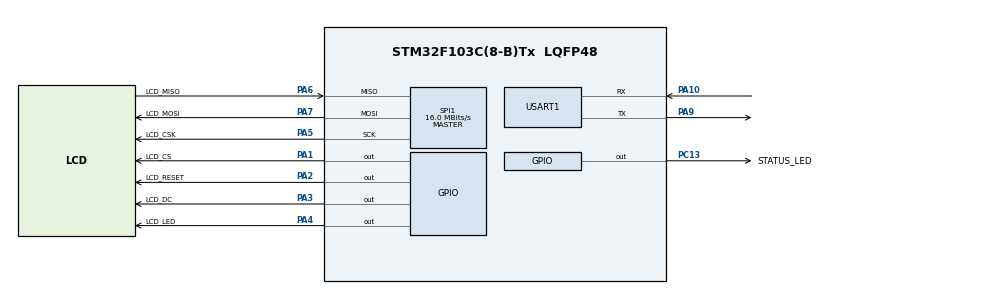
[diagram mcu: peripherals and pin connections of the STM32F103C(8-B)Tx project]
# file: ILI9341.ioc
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Dma.Request0=SPI1_TX
Dma.SPI1_TX.0.Direction=DMA_MEMORY_TO_PERIPH
Dma.SPI1_TX.0.Instance=DMA1_Channel3
Dma.SPI1_TX.0.MemDataAlignment=DMA_MDATAALIGN_BYTE
Dma.SPI1_TX.0.MemInc=DMA_MINC_ENABLE
Dma.SPI1_TX.0.Mode=DMA_NORMAL
Dma.SPI1_TX.0.PeriphDataAlignment=DMA_PDATAALIGN_BYTE
Dma.SPI1_TX.0.PeriphInc=DMA_PINC_DISABLE
Dma.SPI1_TX.0.Priority=DMA_PRIORITY_HIGH
Mcu.Family=STM32F1
Mcu.Name=STM32F103C(8-B)Tx
Mcu.Package=LQFP48
NVIC.DMA1_Channel3_IRQn=true\:0\:0\:false\:false\:true
NVIC.PriorityGroup=NVIC_PRIORITYGROUP_4
PA1.GPIO_Label=LCD_CS
PA1.Signal=GPIO_Output
PA10.Mode=Asynchronous
PA10.Signal=USART1_RX
PA13.Mode=Serial_Wire
PA13.Signal=SYS_JTMS-SWDIO
PA14.Mode=Serial_Wire
PA14.Signal=SYS_JTCK-SWCLK
PA2.GPIO_Label=LCD_RESET
PA2.PinState=GPIO_PIN_RESET
PA2.Signal=GPIO_Output
PA3.GPIO_Label=LCD_DC
PA3.PinState=GPIO_PIN_RESET
PA3.Signal=GPIO_Output
PA4.GPIO_Label=LCD_LED
PA4.Signal=GPIO_Output
PA5.GPIO_Label=LCD_CSK
PA5.Mode=Full_Duplex_Master
PA5.Signal=SPI1_SCK
PA6.GPIO_Label=LCD_MISO
PA6.Mode=Full_Duplex_Master
PA6.Signal=SPI1_MISO
PA7.GPIO_Label=LCD_MOSI
PA7.Mode=Full_Duplex_Master
PA7.Signal=SPI1_MOSI
PA9.Mode=Asynchronous
PA9.Signal=USART1_TX
PC13-TAMPER-RTC.GPIO_Label=STATUS_LED
PC13-TAMPER-RTC.Signal=GPIO_Output
ProjectManager.HeapSize=0x200
ProjectManager.StackSize=0x400
ProjectManager.TargetToolchain=Makefile
RCC.AHBFreq_Value=64000000
RCC.APB1CLKDivider=RCC_HCLK_DIV2
RCC.APB1Freq_Value=32000000
RCC.APB1TimFreq_Value=64000000
RCC.APB2Freq_Value=64000000
RCC.APB2TimFreq_Value=64000000
RCC.HCLKFreq_Value=64000000
RCC.PLLMUL=RCC_PLL_MUL16
RCC.SYSCLKFreq_VALUE=64000000
RCC.SYSCLKSource=RCC_SYSCLKSOURCE_PLLCLK
RCC.USBFreq_Value=64000000
SPI1.BaudRatePrescaler=SPI_BAUDRATEPRESCALER_4
SPI1.CalculateBaudRate=16.0 MBits/s
SPI1.Direction=SPI_DIRECTION_2LINES
SPI1.Mode=SPI_MODE_MASTER
SPI1.VirtualType=VM_MASTER
USART1.VirtualMode=VM_ASYNC
board=ILI9341

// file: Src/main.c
/**
  ******************************************************************************
  * File Name          : main.c
  * Description        : Main program body
  ******************************************************************************
  ** This notice applies to any and all portions of this file
  * that are not between comment pairs USER CODE BEGIN and
  * USER CODE END. Other portions of this file, whether
  * inserted by the user or by software development tools
  * are owned by their respective copyright owners.
  *
  * COPYRIGHT(c) 2017 STMicroelectronics
  *
  * Redistribution and use in source and binary forms, with or without modification,
  * are permitted provided that the following conditions are met:
  *   1. Redistributions of source code must retain the above copyright notice,
  *      this list of conditions and the following disclaimer.
  *   2. Redistributions in binary form must reproduce the above copyright notice,
  *      this list of conditions and the following disclaimer in the documentation
  *      and/or other materials provided with the distribution.
  *   3. Neither the name of STMicroelectronics nor the names of its contributors
  *      may be used to endorse or promote products derived from this software
  *      without specific prior written permission.
  *
  * THIS SOFTWARE IS PROVIDED BY THE COPYRIGHT HOLDERS AND CONTRIBUTORS "AS IS"
  * AND ANY EXPRESS OR IMPLIED WARRANTIES, INCLUDING, BUT NOT LIMITED TO, THE
  * IMPLIED WARRANTIES OF MERCHANTABILITY AND FITNESS FOR A PARTICULAR PURPOSE ARE
  * DISCLAIMED. IN NO EVENT SHALL THE COPYRIGHT HOLDER OR CONTRIBUTORS BE LIABLE
  * FOR ANY DIRECT, INDIRECT, INCIDENTAL, SPECIAL, EXEMPLARY, OR CONSEQUENTIAL
  * DAMAGES (INCLUDING, BUT NOT LIMITED TO, PROCUREMENT OF SUBSTITUTE GOODS OR
  * SERVICES; LOSS OF USE, DATA, OR PROFITS; OR BUSINESS INTERRUPTION) HOWEVER
  * CAUSED AND ON ANY THEORY OF LIABILITY, WHETHER IN CONTRACT, STRICT LIABILITY,
  * OR TORT (INCLUDING NEGLIGENCE OR OTHERWISE) ARISING IN ANY WAY OUT OF THE USE
  * OF THIS SOFTWARE, EVEN IF ADVISED OF THE POSSIBILITY OF SUCH DAMAGE.
  *
  ******************************************************************************
  */
#include "main.h"
#include "stm32f1xx_hal.h"
#include "spi.h"
#include "usart.h"
#include "gpio.h"

/* USER CODE BEGIN Includes */
#include <math.h>
#include "ILI9341.h"

#define M_PI 3.14159

void stled_on(void) {
    HAL_GPIO_WritePin(STATUS_LED_GPIO_Port, STATUS_LED_Pin, GPIO_PIN_SET);
}

void stled_off(void) {
    HAL_GPIO_WritePin(STATUS_LED_GPIO_Port, STATUS_LED_Pin, GPIO_PIN_RESET);
}

/* USER CODE END Includes */

/* USER CODE BEGIN PV */
/* Private variables ---------------------------------------------------------*/

/* USER CODE END PV */

void SystemClock_Config(void);

/* USER CODE BEGIN PFP */
/* Private function prototypes -----------------------------------------------*/

/* USER CODE END PFP */

int main(void)
{

  /* MCU Configuration----------------------------------------------------------*/

  /* Reset of all peripherals, Initializes the Flash interface and the Systick. */
  HAL_Init();

  /* Configure the system clock */
  SystemClock_Config();

  /* Initialize all configured peripherals */
  MX_GPIO_Init();
  MX_SPI1_Init();
  MX_USART1_UART_Init();

  /* USER CODE BEGIN 2 */
  lcd_reset();
  HAL_GPIO_WritePin(GPIOA, LCD_LED_Pin, GPIO_PIN_SET);
  ILI9341_begin(&hspi1);
  ILI9341_setRotation(3);

  /* USER CODE END 2 */

  /* Infinite loop */
  /* USER CODE BEGIN WHILE */
  while (1)
  {
    ILI9341_begin(&hspi1);
    ILI9341_setRotation(3);
  /* USER CODE END WHILE */

  /* USER CODE BEGIN 3 */
    for(uint16_t i = 5; i<315; i+=30)
    {
      ILI9341_drawLine( i, 5, i, 235, ILI9341_OLIVE);
    }
    for(uint16_t i = 5; i<315; i+=30)
    {
      ILI9341_drawLine( 5, i, 315, i, ILI9341_OLIVE);
    }

    for(float i = 0; i < 320; i+=0.2) // count point
    {
      ILI9341_fillCircle(i, 80*sin(30*0.2*M_PI*i/180)+120, 1, ILI9341_GREEN);
      ILI9341_fillCircle(i-50, 80*sin(30*0.2*M_PI*i/180)+120, 1, ILI9341_BLUE);
      ILI9341_fillCircle(i-25, 80*cos(30*M_PI*0.1*i/180)+120, 1, ILI9341_RED);
      ILI9341_fillCircle(i-25, 80*sin(30*M_PI*0.1*i/180)+120, 1, ILI9341_CYAN);
      ILI9341_fillCircle(i, 80*cos(30*0.2*M_PI*i/180)+120, 1, ILI9341_YELLOW);
    }
    lcd_reset();
  }

  /* USER CODE END 3 */

}

/** System Clock Configuration
*/
void SystemClock_Config(void)
{

  RCC_OscInitTypeDef RCC_OscInitStruct;
  RCC_ClkInitTypeDef RCC_ClkInitStruct;

    /**Initializes the CPU, AHB and APB busses clocks
    */
  RCC_OscInitStruct.OscillatorType = RCC_OSCILLATORTYPE_HSI;
  RCC_OscInitStruct.HSIState = RCC_HSI_ON;
  RCC_OscInitStruct.HSICalibrationValue = 16;
  RCC_OscInitStruct.PLL.PLLState = RCC_PLL_NONE;
  if (HAL_RCC_OscConfig(&RCC_OscInitStruct) != HAL_OK)
  {
    _Error_Handler(__FILE__, __LINE__);
  }

    /**Initializes the CPU, AHB and APB busses clocks
    */
  RCC_ClkInitStruct.ClockType = RCC_CLOCKTYPE_HCLK|RCC_CLOCKTYPE_SYSCLK
                              |RCC_CLOCKTYPE_PCLK1|RCC_CLOCKTYPE_PCLK2;
  RCC_ClkInitStruct.SYSCLKSource = RCC_SYSCLKSOURCE_HSI;
  RCC_ClkInitStruct.AHBCLKDivider = RCC_SYSCLK_DIV1;
  RCC_ClkInitStruct.APB1CLKDivider = RCC_HCLK_DIV1;
  RCC_ClkInitStruct.APB2CLKDivider = RCC_HCLK_DIV1;

  if (HAL_RCC_ClockConfig(&RCC_ClkInitStruct, FLASH_LATENCY_0) != HAL_OK)
  {
    _Error_Handler(__FILE__, __LINE__);
  }

    /**Configure the Systick interrupt time
    */
  HAL_SYSTICK_Config(HAL_RCC_GetHCLKFreq()/1000);

    /**Configure the Systick
    */
  HAL_SYSTICK_CLKSourceConfig(SYSTICK_CLKSOURCE_HCLK);

  /* SysTick_IRQn interrupt configuration */
  HAL_NVIC_SetPriority(SysTick_IRQn, 0, 0);
}

void _Error_Handler(char * file, int line)
{
  while(1)
  {
  }
}

/************************ (C) COPYRIGHT STMicroelectronics *****END OF FILE****/
